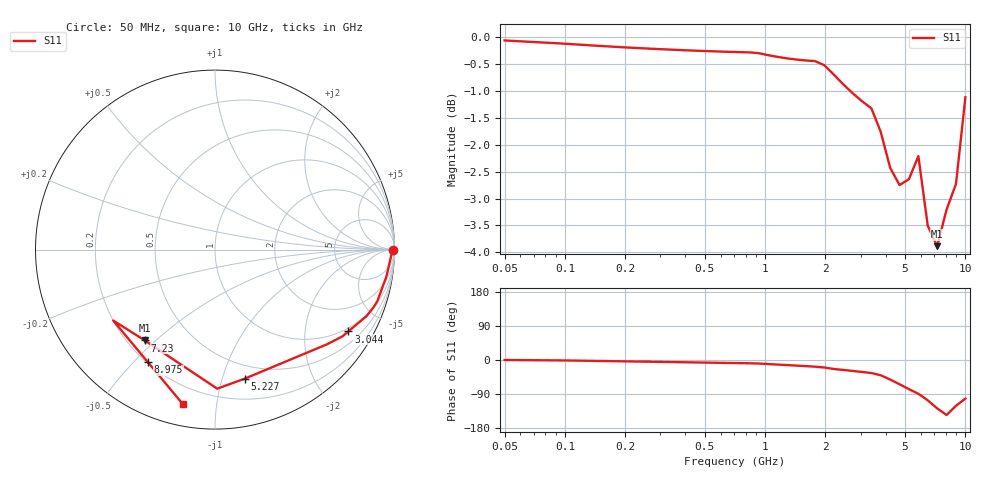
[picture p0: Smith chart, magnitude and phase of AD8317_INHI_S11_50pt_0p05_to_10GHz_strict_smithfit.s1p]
! AD8317 INHI/INLO input model, 0.05-10 GHz
! Sources: AD8317 Rev.D pp.3-4 impedance table + p.9 Figure 15 approximation
! INLO is RF common (AC-coupled to ground), modeled implicitly in single-ended S11 at INHI.
# GHZ S RI R 50
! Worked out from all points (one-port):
!   50 points, 50 MHz to 10 GHz, reference 50 ohm
!   lowest |S11| = -3.9 dB at 7.23 GHz (marker M1), VSWR 4.55, Z = 13.5 - j23.1 ohm
!   |S11| at or under -10 dB: nowhere
!   S11 on the Smith chart (normalised r, x): 50 MHz: open; 3.044 GHz: 0.88, -3.33; 5.227 GHz: 0.38, -1.19; 7.23 GHz: 0.27, -0.46; 8.975 GHz: 0.20, -0.55; 10 GHz: 0.11, -0.81
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0.05  0.992 0
0.09566  0.9854 -0.0187
0.106583  0.9841 -0.0238
0.203914  0.9753 -0.0622
0.390127  0.9664 -0.1005
0.746388  0.9576 -0.1389
0.83162  0.9561 -0.1453
0.926583  0.9529 -0.1558
1.150281  0.9369 -0.1993
1.427985  0.921 -0.2427
1.591049  0.9131 -0.2644
1.772733  0.9051 -0.2861
1.975164  0.8854 -0.3185
2.20071  0.8449 -0.3701
2.452012  0.8109 -0.3986
2.732011  0.7768 -0.4272
3.043983  0.7428 -0.4557
3.39158  0.7088 -0.4843
3.778869  0.6219 -0.5285
4.210383  0.47 -0.592
4.691173  0.3181 -0.6554
5.226864  0.1662 -0.7189
5.823727  0.0124 -0.7749
6.488747  -0.1894 -0.6404
7.229706  -0.3911 -0.5059
8.055276  -0.5677 -0.3948
8.975119  -0.3738 -0.6274
10  -0.18 -0.86
